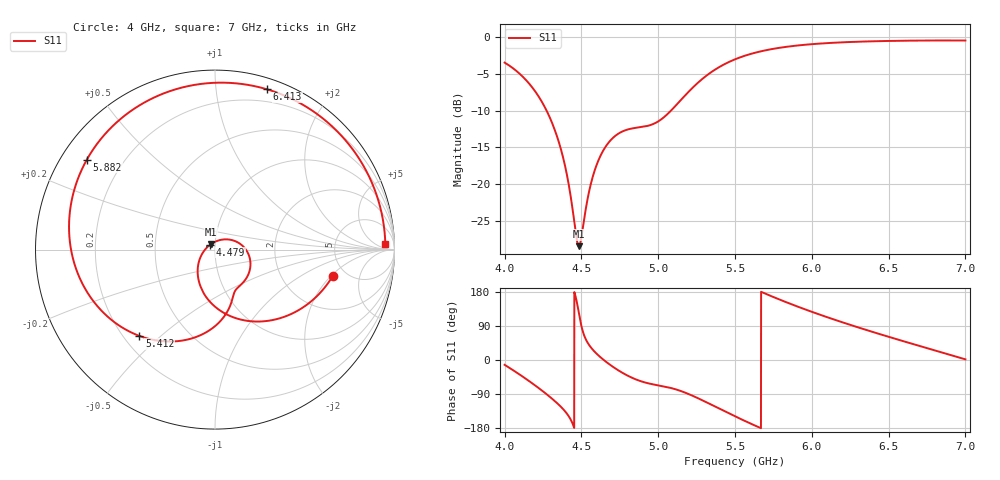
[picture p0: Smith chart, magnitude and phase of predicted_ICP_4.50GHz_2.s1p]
! ICP-predicted S11, target max centred GHz at -10 dB. Complex ensemble mean (passive and causal);
! its |S11| can differ slightly from the dB-domain mean reported in designs.csv.
!  Air_gap = 3.81mm
!  W_Patch = 16.68mm
!  L_Patch = 21.41mm
!  Sx = 1.03mm
!  Sy = 0.37mm
!  W_Patch1 = 9.63mm
!  WS = 0.99mm
!  Curve_Amp1 = 1.15mm
!  Extra = 7.12mm
# GHz S MA R 50
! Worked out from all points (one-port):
!   3001 points, 4 GHz to 7 GHz, reference 50 ohm
!   lowest |S11| = -28.4 dB at 4.483 GHz (marker M1), VSWR 1.08, Z = 47.8 + j2.98 ohm
!   |S11| at or under -10 dB: 4.274 GHz to 5.083 GHz (808.9 MHz wide, 17.3 % of centre)
!   S11 on the Smith chart (normalised r, x): 4 GHz: 3.90, -2.10; 4.479 GHz: 0.95, +0.05; 5.412 GHz: 0.26, -0.43; 5.882 GHz: 0.07, +0.31; 6.413 GHz: 0.09, +1.37; 7 GHz: 29, +17
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4  0.672 -12.7
4.096  0.5665 -37.8
4.177  0.4596 -60.7
4.284  0.3003 -93.7
4.375  0.1606 -127.0
4.414  0.1044 -146.3
4.479  0.03835 134.0
4.483  0.03793 124.9
4.499  0.04303 91.4
4.555  0.09418 36.8
4.599  0.1354 16.6
4.666  0.1854 -6.5
4.75  0.2239 -29.7
4.981  0.2608 -65.4
5.125  0.3525 -78.8
5.29  0.5231 -106.8
5.412  0.6392 -131.2
5.5  0.7072 -148.6
5.594  0.7651 -166.4
5.684  0.8084 177.5
5.875  0.8707 146.0
5.882  0.8725 144.9
6.068  0.9073 117.4
6.25  0.9277 92.8
6.413  0.939 72.0
6.625  0.9472 46.1
6.817  0.9502 23.4
7  0.9494 1.7
